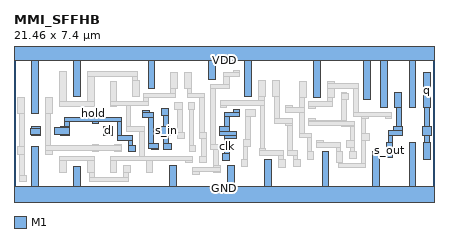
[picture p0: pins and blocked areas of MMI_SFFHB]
MACRO MMI_SFFHB
	CLASS CORE ;
	FOREIGN MMI_SFFHB 0 0 ;
	SIZE 21.46 BY 7.4 ;
	SYMMETRY X Y ;
	SITE CORE1 ;
	PIN d
		DIRECTION input ;
		USE SIGNAL ;
		PORT
			LAYER M1 ;
			RECT 4.585 3.105 5.035 3.555 ;
		END
		AntennaGateArea 0.4968 ;
	END d
	PIN GND
		DIRECTION inout ;
		USE GROUND ;
		PORT
			LAYER M1 ;
			RECT 0.9 0.5 1.24 2.515 ;
			LAYER M1 ;
			RECT 3.04 0.5 3.38 1.53 ;
			LAYER M1 ;
			RECT 7.95 0.5 8.29 1.57 ;
			LAYER M1 ;
			RECT 10.91 0.5 11.25 1.57 ;
			LAYER M1 ;
			RECT 12.8 0.5 13.14 1.84 ;
			LAYER M1 ;
			RECT 15.74 0.5 16.08 2.25 ;
			LAYER M1 ;
			RECT 18.31 0.5 18.65 2.25 ;
			LAYER M1 ;
			RECT 20.2 0.5 20.54 2.73 ;
			LAYER M1 ;
			RECT 0 -0.5 21.46 0.5 ;
		END
	END GND
	PIN q
		DIRECTION output ;
		USE SIGNAL ;
		PORT
			LAYER M1 ;
			RECT 20.92 4.535 21.26 6.295 ;
			LAYER M1 ;
			RECT 20.975 3.555 21.205 4.535 ;
			LAYER M1 ;
			RECT 20.865 3.105 21.315 3.555 ;
			LAYER M1 ;
			RECT 20.975 2.73 21.205 3.105 ;
			LAYER M1 ;
			RECT 20.92 1.89 21.26 2.73 ;
		END
		AntennaDiffArea 1.3248 ;
	END q
	PIN s_en
		DIRECTION input ;
		USE SIGNAL ;
		PORT
			LAYER M1 ;
			RECT 6.58 4.26 6.92 4.38 ;
			LAYER M1 ;
			RECT 6.58 4.03 7.115 4.26 ;
			LAYER M1 ;
			RECT 0.885 3.47 1.335 3.555 ;
			LAYER M1 ;
			RECT 0.83 3.13 1.335 3.47 ;
			LAYER M1 ;
			RECT 0.885 3.105 1.335 3.13 ;
			LAYER M1 ;
			RECT 6.885 2.7 7.115 4.03 ;
			LAYER M1 ;
			RECT 6.885 2.415 7.38 2.7 ;
			LAYER M1 ;
			RECT 7.04 2.36 7.38 2.415 ;
		END
		AntennaGateArea 1.296 ;
	END s_en
	PIN s_in
		DIRECTION input ;
		USE SIGNAL ;
		PORT
			LAYER M1 ;
			RECT 7.535 4.125 7.875 4.465 ;
			LAYER M1 ;
			RECT 7.645 3.555 7.875 4.125 ;
			LAYER M1 ;
			RECT 7.545 3.105 7.995 3.555 ;
			LAYER M1 ;
			RECT 7.645 2.7 7.875 3.105 ;
			LAYER M1 ;
			RECT 7.645 2.36 8.05 2.7 ;
		END
		AntennaGateArea 0.2484 ;
	END s_in
	PIN VDD
		DIRECTION inout ;
		USE POWER ;
		PORT
			LAYER M1 ;
			RECT 0 6.9 21.46 7.9 ;
			LAYER M1 ;
			RECT 0.9 4.2 1.24 6.9 ;
			LAYER M1 ;
			RECT 3.04 5.065 3.38 6.9 ;
			LAYER M1 ;
			RECT 6.86 5.475 7.2 6.9 ;
			LAYER M1 ;
			RECT 9.96 5.975 10.3 6.9 ;
			LAYER M1 ;
			RECT 11.77 5.105 12.11 6.9 ;
			LAYER M1 ;
			RECT 15.31 5.035 15.65 6.9 ;
			LAYER M1 ;
			RECT 17.88 4.91 18.22 6.9 ;
			LAYER M1 ;
			RECT 18.72 4.535 19.06 6.9 ;
			LAYER M1 ;
			RECT 20.2 4.535 20.54 6.9 ;
		END
	END VDD
	PIN s_out
		DIRECTION output ;
		USE SIGNAL ;
		PORT
			LAYER M1 ;
			RECT 19.44 4.535 19.78 5.295 ;
			LAYER M1 ;
			RECT 19.55 3.555 19.78 4.535 ;
			LAYER M1 ;
			RECT 19.385 3.335 19.835 3.555 ;
			LAYER M1 ;
			RECT 19.12 3.105 19.835 3.335 ;
			LAYER M1 ;
			RECT 19.12 2.73 19.35 3.105 ;
			LAYER M1 ;
			RECT 19.01 1.97 19.35 2.73 ;
		END
		AntennaDiffArea 0.8568 ;
	END s_out
	PIN clk
		DIRECTION input ;
		USE CLOCK ;
		PORT
			LAYER M1 ;
			RECT 11.2 4.29 11.54 4.4 ;
			LAYER M1 ;
			RECT 10.78 4.06 11.54 4.29 ;
			LAYER M1 ;
			RECT 10.78 3.555 11.01 4.06 ;
			LAYER M1 ;
			RECT 10.505 3.28 11.01 3.555 ;
			LAYER M1 ;
			RECT 10.505 3.105 11.35 3.28 ;
			LAYER M1 ;
			RECT 10.78 2.94 11.35 3.105 ;
			LAYER M1 ;
			RECT 10.78 2.15 11.01 2.94 ;
			LAYER M1 ;
			RECT 10.67 1.81 11.01 2.15 ;
		END
		AntennaGateArea 0.6408 ;
	END clk
	PIN hold
		DIRECTION input ;
		USE SIGNAL ;
		PORT
			LAYER M1 ;
			RECT 4 4.015 4.34 4.025 ;
			LAYER M1 ;
			RECT 2.585 3.785 5.51 4.015 ;
			LAYER M1 ;
			RECT 2.585 3.555 2.815 3.785 ;
			LAYER M1 ;
			RECT 4 3.685 4.34 3.785 ;
			LAYER M1 ;
			RECT 2.365 3.495 2.815 3.555 ;
			LAYER M1 ;
			RECT 2.085 3.155 2.815 3.495 ;
			LAYER M1 ;
			RECT 2.365 3.105 2.815 3.155 ;
			LAYER M1 ;
			RECT 5.28 3.085 5.51 3.785 ;
			LAYER M1 ;
			RECT 5.28 2.855 6.08 3.085 ;
			LAYER M1 ;
			RECT 5.85 2.6 6.08 2.855 ;
			LAYER M1 ;
			RECT 5.85 2.26 6.19 2.6 ;
		END
		AntennaGateArea 0.7452 ;
	END hold
	OBS
		LAYER M1 ;
		RECT 0.18 4.2 0.52 5.04 ;
		LAYER M1 ;
		RECT 1.62 4.2 1.96 5.04 ;
		LAYER M1 ;
		RECT 2.32 4.815 2.66 6.345 ;
		LAYER M1 ;
		RECT 3.76 6.115 6.29 6.345 ;
		LAYER M1 ;
		RECT 3.76 4.815 4.1 6.115 ;
		LAYER M1 ;
		RECT 6.06 5.885 6.29 6.115 ;
		LAYER M1 ;
		RECT 2.32 4.585 4.1 4.815 ;
		LAYER M1 ;
		RECT 4.91 4.84 5.25 5.865 ;
		LAYER M1 ;
		RECT 6.06 5.075 6.4 5.885 ;
		LAYER M1 ;
		RECT 8.01 5.475 8.35 6.315 ;
		LAYER M1 ;
		RECT 8.73 5.475 9.07 6.315 ;
		LAYER M1 ;
		RECT 11.2 6.32 11.54 6.43 ;
		LAYER M1 ;
		RECT 10.68 6.09 11.54 6.32 ;
		LAYER M1 ;
		RECT 10.68 5.705 11.02 6.09 ;
		LAYER M1 ;
		RECT 8.01 5.245 8.24 5.475 ;
		LAYER M1 ;
		RECT 6.63 5.015 8.24 5.245 ;
		LAYER M1 ;
		RECT 8.84 5.245 9.07 5.475 ;
		LAYER M1 ;
		RECT 10.045 5.475 11.02 5.705 ;
		LAYER M1 ;
		RECT 8.84 5.015 9.72 5.245 ;
		LAYER M1 ;
		RECT 6.63 4.84 6.86 5.015 ;
		LAYER M1 ;
		RECT 4.91 4.61 6.86 4.84 ;
		LAYER M1 ;
		RECT 4.91 4.585 5.25 4.61 ;
		LAYER M1 ;
		RECT 0.29 2.515 0.52 4.2 ;
		LAYER M1 ;
		RECT 1.62 2.57 1.85 4.2 ;
		LAYER M1 ;
		RECT 5.74 3.545 5.97 4.61 ;
		LAYER M1 ;
		RECT 8.215 4.445 8.585 4.785 ;
		LAYER M1 ;
		RECT 8.9 4.445 9.24 4.785 ;
		LAYER M1 ;
		RECT 5.74 3.315 6.655 3.545 ;
		LAYER M1 ;
		RECT 4 2.57 4.34 2.625 ;
		LAYER M1 ;
		RECT 5.15 2.57 5.49 2.615 ;
		LAYER M1 ;
		RECT 0.18 2.135 0.52 2.515 ;
		LAYER M1 ;
		RECT 0.29 1.07 0.52 2.135 ;
		LAYER M1 ;
		RECT 0.29 0.73 0.63 1.07 ;
		LAYER M1 ;
		RECT 1.62 2.34 5.49 2.57 ;
		LAYER M1 ;
		RECT 1.62 2.135 1.96 2.34 ;
		LAYER M1 ;
		RECT 4 2.285 4.34 2.34 ;
		LAYER M1 ;
		RECT 5.15 2.275 5.49 2.34 ;
		LAYER M1 ;
		RECT 6.425 2.03 6.655 3.315 ;
		LAYER M1 ;
		RECT 8.355 3.27 8.585 4.445 ;
		LAYER M1 ;
		RECT 8.355 2.93 8.72 3.27 ;
		LAYER M1 ;
		RECT 8.95 2.6 9.18 4.445 ;
		LAYER M1 ;
		RECT 9.49 3.27 9.72 5.015 ;
		LAYER M1 ;
		RECT 9.475 2.93 9.815 3.27 ;
		LAYER M1 ;
		RECT 8.95 2.26 9.29 2.6 ;
		LAYER M1 ;
		RECT 9.585 2.03 9.815 2.93 ;
		LAYER M1 ;
		RECT 10.045 2.61 10.275 5.475 ;
		LAYER M1 ;
		RECT 12.49 5.075 12.83 5.915 ;
		LAYER M1 ;
		RECT 13.21 5.075 13.55 5.915 ;
		LAYER M1 ;
		RECT 10.53 4.86 10.87 4.865 ;
		LAYER M1 ;
		RECT 12.49 4.86 12.81 5.075 ;
		LAYER M1 ;
		RECT 10.53 4.63 12.81 4.86 ;
		LAYER M1 ;
		RECT 10.53 4.525 10.87 4.63 ;
		LAYER M1 ;
		RECT 11.83 4.06 12.35 4.4 ;
		LAYER M1 ;
		RECT 10.045 2.38 10.44 2.61 ;
		LAYER M1 ;
		RECT 2.32 1.8 4.1 2.03 ;
		LAYER M1 ;
		RECT 2.32 1.19 2.66 1.8 ;
		LAYER M1 ;
		RECT 3.76 1.19 4.1 1.8 ;
		LAYER M1 ;
		RECT 4.91 1.8 9.11 2.03 ;
		LAYER M1 ;
		RECT 4.91 1.19 5.25 1.8 ;
		LAYER M1 ;
		RECT 5.61 1.195 5.95 1.535 ;
		LAYER M1 ;
		RECT 3.87 0.96 4.1 1.19 ;
		LAYER M1 ;
		RECT 5.61 0.96 5.84 1.195 ;
		LAYER M1 ;
		RECT 6.76 1.19 7.1 1.8 ;
		LAYER M1 ;
		RECT 8.77 1.69 9.11 1.8 ;
		LAYER M1 ;
		RECT 9.49 1.69 9.83 2.03 ;
		LAYER M1 ;
		RECT 10.21 1.57 10.44 2.38 ;
		LAYER M1 ;
		RECT 11.83 2.875 12.06 4.06 ;
		LAYER M1 ;
		RECT 11.72 2.505 12.06 2.875 ;
		LAYER M1 ;
		RECT 11.72 1.84 11.95 2.505 ;
		LAYER M1 ;
		RECT 12.58 2.415 12.81 4.63 ;
		LAYER M1 ;
		RECT 13.32 3.95 13.55 5.075 ;
		LAYER M1 ;
		RECT 14.59 5.035 14.93 5.875 ;
		LAYER M1 ;
		RECT 16.03 5.745 16.37 5.875 ;
		LAYER M1 ;
		RECT 16.03 5.515 17.585 5.745 ;
		LAYER M1 ;
		RECT 16.03 5.035 16.37 5.515 ;
		LAYER M1 ;
		RECT 16.75 5.25 16.98 5.275 ;
		LAYER M1 ;
		RECT 13.89 4.51 14.23 4.62 ;
		LAYER M1 ;
		RECT 14.595 4.51 14.825 5.035 ;
		LAYER M1 ;
		RECT 16.03 4.805 16.26 5.035 ;
		LAYER M1 ;
		RECT 16.73 4.91 17.07 5.25 ;
		LAYER M1 ;
		RECT 13.89 4.28 14.825 4.51 ;
		LAYER M1 ;
		RECT 15.07 4.575 16.26 4.805 ;
		LAYER M1 ;
		RECT 15.07 4.465 15.41 4.575 ;
		LAYER M1 ;
		RECT 13.32 3.72 14.23 3.95 ;
		LAYER M1 ;
		RECT 13.89 3.61 14.23 3.72 ;
		LAYER M1 ;
		RECT 12.52 2.305 12.86 2.415 ;
		LAYER M1 ;
		RECT 14 2.305 14.23 3.61 ;
		LAYER M1 ;
		RECT 14.595 3.2 14.825 4.28 ;
		LAYER M1 ;
		RECT 15.055 3.84 15.395 3.95 ;
		LAYER M1 ;
		RECT 16.75 3.84 16.98 4.91 ;
		LAYER M1 ;
		RECT 17.355 4.29 17.585 5.515 ;
		LAYER M1 ;
		RECT 17.355 4.06 19.3 4.29 ;
		LAYER M1 ;
		RECT 15.055 3.795 16.98 3.84 ;
		LAYER M1 ;
		RECT 17.74 3.95 18.105 4.06 ;
		LAYER M1 ;
		RECT 18.96 3.95 19.3 4.06 ;
		LAYER M1 ;
		RECT 15.055 3.61 17.415 3.795 ;
		LAYER M1 ;
		RECT 16.75 3.565 17.415 3.61 ;
		LAYER M1 ;
		RECT 14.595 2.97 15.21 3.2 ;
		LAYER M1 ;
		RECT 12.52 2.075 13.75 2.305 ;
		LAYER M1 ;
		RECT 14 2.075 14.51 2.305 ;
		LAYER M1 ;
		RECT 13.52 1.84 13.75 2.075 ;
		LAYER M1 ;
		RECT 14.28 1.84 14.51 2.075 ;
		LAYER M1 ;
		RECT 14.98 2.25 15.21 2.97 ;
		LAYER M1 ;
		RECT 17.185 2.82 17.415 3.565 ;
		LAYER M1 ;
		RECT 15.46 2.71 15.8 2.82 ;
		LAYER M1 ;
		RECT 15.46 2.48 16.69 2.71 ;
		LAYER M1 ;
		RECT 16.965 2.48 17.415 2.82 ;
		LAYER M1 ;
		RECT 16.46 2.25 16.69 2.48 ;
		LAYER M1 ;
		RECT 17.185 2.25 17.415 2.48 ;
		LAYER M1 ;
		RECT 17.74 3.17 17.97 3.95 ;
		LAYER M1 ;
		RECT 17.74 2.83 18.17 3.17 ;
		LAYER M1 ;
		RECT 14.98 1.87 15.32 2.25 ;
		LAYER M1 ;
		RECT 3.87 0.73 5.84 0.96 ;
		LAYER M1 ;
		RECT 10.19 1.46 10.53 1.57 ;
		LAYER M1 ;
		RECT 9.13 1.23 10.53 1.46 ;
		LAYER M1 ;
		RECT 9.13 1.12 9.47 1.23 ;
		LAYER M1 ;
		RECT 10.19 1.19 10.53 1.23 ;
		LAYER M1 ;
		RECT 11.61 1.5 11.95 1.84 ;
		LAYER M1 ;
		RECT 13.52 1.46 13.86 1.84 ;
		LAYER M1 ;
		RECT 14.28 1.5 14.62 1.84 ;
		LAYER M1 ;
		RECT 16.46 1.71 16.8 2.25 ;
		LAYER M1 ;
		RECT 17.16 1.91 17.5 2.25 ;
		LAYER M1 ;
		RECT 16.57 1.665 16.8 1.71 ;
		LAYER M1 ;
		RECT 17.74 1.665 17.97 2.83 ;
		LAYER M1 ;
		RECT 16.57 1.435 17.97 1.665 ;
	END
END MMI_SFFHB
